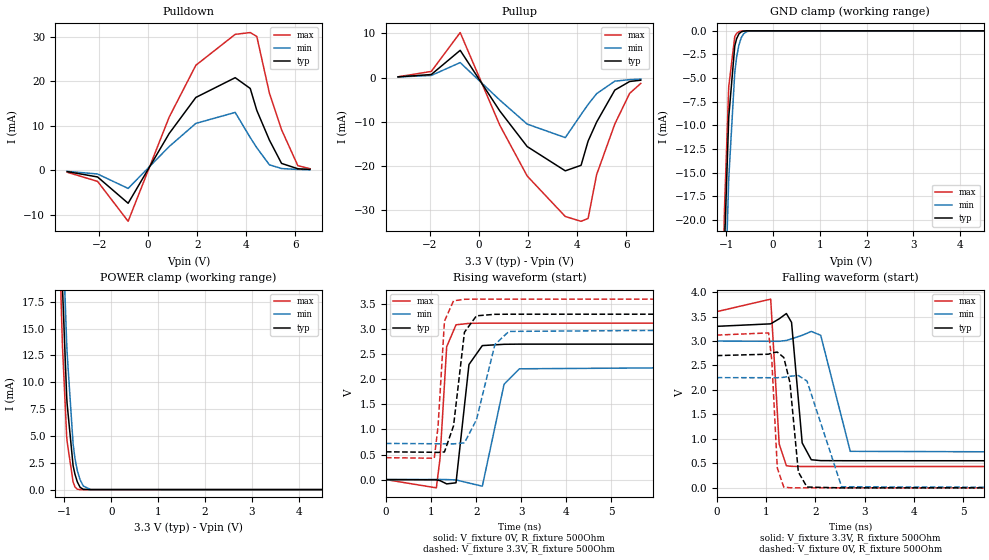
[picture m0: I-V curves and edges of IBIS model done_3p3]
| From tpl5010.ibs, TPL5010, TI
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|   Model
[Model]   done_3p3
Model_type   I/O
Polarity   Non-Inverting
Enable   Active-Low
Vinl = 0.99
Vinh = 2.31
Vmeas = 1.65
Vref = 0
Cref = 1pF
Rref = 100000
|   typ   min   max
C_comp   0.333pF   0.286pF   0.375pF
[Voltage Range]   3.3   3   3.6
[Temperature Range]   25   105   -40
[Pullup Reference]   3.3   3   3.6
[Pulldown Reference]   0   0   0
[Power Clamp Reference]   3.3   3   3.6
[GND Clamp Reference]   0   0   0
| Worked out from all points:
|   slope of the pulldown table from 0 to 0.495 V, typ, clamps not added: 100 ohm
|   slope of the pullup table from 0 to 0.495 V, typ, clamps not added: 110 ohm
|   GND clamp passes 1 mA (typ) near -0.79 V on its own axis
|   POWER clamp passes 1 mA (typ) near -0.75 V on its own axis
|   falling waveform, V_fixture 3.3V, R_fixture 500Ohm: 20-80 % time 129ps typ, 199ps min, 89.4ps max; typ from 3.3 V to 0.554 V
|   rising waveform, V_fixture 0V, R_fixture 500Ohm: 20-80 % time 166ps typ, 249ps min, 116ps max; typ from 0 V to 2.7 V
|   rising waveform, V_fixture 3.3V, R_fixture 500Ohm: 20-80 % time 200ps typ, 363ps min, 120ps max; typ from 0.554 V to 3.3 V
|   falling waveform, V_fixture 0V, R_fixture 500Ohm: 20-80 % time 142ps typ, 260ps min, 87.8ps max; typ from 2.7 V to 0 V
[Pulldown]
|   Voltage   I(typ)   I(min)   I(max)
-3.3V     -260.4uA   -210.9uA   -408.3uA
-2.062V   -1.464mA   -801.8uA   -2.457mA
-815.1mV  -7.364mA   -4.037mA   -11.41mA
858mV     8.275mA    5.351mA    11.95mA
1.947V    16.37mA    10.55mA    23.59mA
3.551V    20.8mA     13.01mA    30.52mA
4.165V    18.38mA    7.371mA    30.92mA
4.432V    13.47mA    5.083mA    30.05mA
4.947V    6.799mA    1.26mA     17.34mA
5.442V    1.575mA    421.1uA    9.133mA
6.105V    375.7uA    216.6uA    1.069mA
6.6V      227.9uA    150.4uA    386.2uA
[GND Clamp]
|   Voltage   I(typ)   I(min)   I(max)
-3.3V     -836.6mA   -780.4mA   -895mA
-1.043V   -24.52mA   -32.26mA   -20.67mA
-1.033V   -22.55mA   -30.3mA    -18.64mA
-943.8mV  -9.134mA   -15.65mA   -5.921mA
-815.1mV  -1.607mA   -4.399mA   -599.1uA
-775.5mV  -830.2uA   -2.781mA   -264.4uA
-726mV    -319.3uA   -1.488mA   -92.99uA
-676.5mV  -109.3uA   -730.3uA   -28.86uA
-627mV    -34.32uA   -315.6uA   -7.336uA
-557.7mV  -5.789uA   -75.32uA   -818.5nA
-458.7mV  -345.8nA   -6.679uA   -11.63nA
6.6V      0A         0A         0A
[Pullup]
|   Voltage   I(typ)   I(min)   I(max)
-3.3V     156.8uA    141.8uA    181.5uA
-1.944V   690.4uA    480.5uA    1.383mA
-765.6mV  6.15mA     3.383mA    10.16mA
848.1mV   -7.519mA   -5.069mA   -10.74mA
1.967V    -15.57mA   -10.5mA    -22.22mA
3.521V    -21.05mA   -13.55mA   -31.36mA
4.165V    -19.8mA    -8.341mA   -32.44mA
4.452V    -14.33mA   -6.061mA   -31.8mA
4.798V    -10.06mA   -3.637mA   -21.92mA
5.541V    -2.825mA   -804.4uA   -10.48mA
6.145V    -885.6uA   -469.2uA   -3.565mA
6.6V      -592.9uA   -349.3uA   -1.316mA
[POWER Clamp]
|   Voltage   I(typ)   I(min)   I(max)
-3.3V     582mA      540.9mA    621.3mA
-1.073V   23.41mA    29.24mA    17.84mA
-1.043V   18.92mA    24.81mA    13.46mA
-953.7mV  8.825mA    13.77mA    5.051mA
-943.8mV  8.035mA    12.78mA    4.501mA
-815.1mV  2.227mA    4.236mA    714.5uA
-775.5mV  1.434mA    2.91mA     248.9uA
-726mV    730.7uA    1.778mA    36.03uA
-666.6mV  216.1uA    916.7uA    2.519uA
-597.3mV  24.37uA    334uA      111.5nA
-438.9mV  67.46nA    6.719uA    0A
6.6V      0A         0A         0A
[Ramp]
R_load = 500
|   typ   min   max
dV/dt_r   1.62128/1.65346e-10   1.3513/2.47617e-10   1.87269/1.15458e-10
dV/dt_f   1.64786/1.29326e-10   1.36721/1.99127e-10   1.89813/8.9369e-11
[Falling Waveform]
V_fixture = 3.3V
V_fixture_min = 3V
V_fixture_max = 3.6V
R_fixture = 500Ohm
C_fixture = 0F
|   Time   V(typ)   V(min)   V(max)
0s        3.3V       3V         3.6V
1.095ns   3.351V     2.995V     3.856V
1.267ns   3.454V     2.994V     897.3mV
1.413ns   3.562V     3.012V     452.4mV
1.518ns   3.381V     3.045V     439.4mV
1.734ns   917.3mV    3.117V     436.6mV
1.918ns   574.7mV    3.196V     436.5mV
2.11ns    556.2mV    3.117V     436.5mV
2.709ns   554mV      746.5mV    436.5mV
10ns      553.6mV    721.3mV    436.4mV
[Rising Waveform]
V_fixture = 0V
V_fixture_min = 0V
V_fixture_max = 0V
R_fixture = 500Ohm
C_fixture = 0F
|   Time   V(typ)   V(min)   V(max)
0s        -226.8nV   176.2nV    -193.5nV
1.118ns   -5.569mV   1.916mV    -165.3mV
1.199ns   -20.84mV   2.055mV    413.9mV
1.347ns   -86.23mV   -217.3uV   2.651V
1.554ns   -64.29mV   -6.767mV   3.088V
1.841ns   2.295V     -69.04mV   3.116V
2.137ns   2.673V     -132.4mV   3.121V
2.619ns   2.699V     1.901V     3.121V
2.959ns   2.702V     2.21V      3.121V
10ns      2.702V     2.252V     3.121V
[Rising Waveform]
V_fixture = 3.3V
V_fixture_min = 3V
V_fixture_max = 3.6V
R_fixture = 500Ohm
C_fixture = 0F
|   Time   V(typ)   V(min)   V(max)
0s        553.6mV    721.3mV    436.4mV
1.072ns   544.6mV    714.7mV    426mV
1.155ns   541.6mV    714.2mV    1.052V
1.298ns   551.4mV    713.3mV    3.162V
1.499ns   1.072V     712.1mV    3.567V
1.741ns   2.94V      731.7mV    3.597V
2.007ns   3.267V     1.195V     3.6V
2.416ns   3.297V     2.695V     3.6V
2.726ns   3.299V     2.956V     3.6V
10ns      3.3V       3V         3.6V
[Falling Waveform]
|Gnd
V_fixture = 0V
V_fixture_min = 0V
V_fixture_max = 0V
R_fixture = 500Ohm
C_fixture = 0F
|   Time   V(typ)   V(min)   V(max)
0s        2.702V     2.252V     3.121V
1.052ns   2.731V     2.25V      3.166V
1.118ns   2.759V     2.25V      2.6V
1.229ns   2.774V     2.25V      403.8mV
1.361ns   2.663V     2.259V     15.07mV
1.485ns   2.151V     2.281V     2.481mV
1.656ns   323.7mV    2.295V     181.8uV
1.831ns   16.67mV    2.183V     178uV
2.534ns   118.4uV    21.75mV    162.7uV
10ns      255.3nV    -144.9nV   237.4nV
